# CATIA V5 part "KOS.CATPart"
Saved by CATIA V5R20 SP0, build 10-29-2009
Part number: KOS
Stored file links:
  C:\Users\Andi\Desktop\Plasma\KOS.CATPart

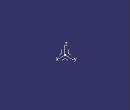
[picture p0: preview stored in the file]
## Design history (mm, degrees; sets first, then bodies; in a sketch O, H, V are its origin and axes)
AxisSystem1: origin (0, 0, 0), X (1, 0, 0), Y (0, 1, 0), Z (0, 0, 1)
Body1 (main body)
